VERSION 5.7 ;
  NOWIREEXTENSIONATPIN ON ;
  DIVIDERCHAR "/" ;
  BUSBITCHARS "[]" ;
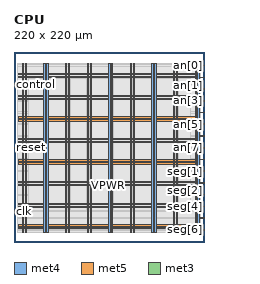
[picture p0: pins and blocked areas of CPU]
MACRO CPU
  CLASS BLOCK ;
  FOREIGN CPU ;
  ORIGIN 0.000 0.000 ;
  SIZE 220.000 BY 220.000 ;
  PIN VGND
    DIRECTION INOUT ;
    USE GROUND ;
    PORT
      LAYER met4 ;
        RECT 13.020 10.640 14.620 206.960 ;
    END
    PORT
      LAYER met4 ;
        RECT 38.020 10.640 39.620 206.960 ;
    END
    PORT
      LAYER met4 ;
        RECT 63.020 10.640 64.620 206.960 ;
    END
    PORT
      LAYER met4 ;
        RECT 88.020 10.640 89.620 206.960 ;
    END
    PORT
      LAYER met4 ;
        RECT 113.020 10.640 114.620 206.960 ;
    END
    PORT
      LAYER met4 ;
        RECT 138.020 10.640 139.620 206.960 ;
    END
    PORT
      LAYER met4 ;
        RECT 163.020 10.640 164.620 206.960 ;
    END
    PORT
      LAYER met4 ;
        RECT 188.020 10.640 189.620 206.960 ;
    END
    PORT
      LAYER met4 ;
        RECT 213.020 10.640 214.620 206.960 ;
    END
    PORT
      LAYER met5 ;
        RECT 5.280 18.380 214.620 19.980 ;
    END
    PORT
      LAYER met5 ;
        RECT 5.280 43.380 214.620 44.980 ;
    END
    PORT
      LAYER met5 ;
        RECT 5.280 68.380 214.620 69.980 ;
    END
    PORT
      LAYER met5 ;
        RECT 5.280 93.380 214.620 94.980 ;
    END
    PORT
      LAYER met5 ;
        RECT 5.280 118.380 214.620 119.980 ;
    END
    PORT
      LAYER met5 ;
        RECT 5.280 143.380 214.620 144.980 ;
    END
    PORT
      LAYER met5 ;
        RECT 5.280 168.380 214.620 169.980 ;
    END
    PORT
      LAYER met5 ;
        RECT 5.280 193.380 214.620 194.980 ;
    END
  END VGND
  PIN VPWR
    DIRECTION INOUT ;
    USE POWER ;
    PORT
      LAYER met4 ;
        RECT 9.720 10.640 11.320 206.960 ;
    END
    PORT
      LAYER met4 ;
        RECT 34.720 10.640 36.320 206.960 ;
    END
    PORT
      LAYER met4 ;
        RECT 59.720 10.640 61.320 206.960 ;
    END
    PORT
      LAYER met4 ;
        RECT 84.720 10.640 86.320 206.960 ;
    END
    PORT
      LAYER met4 ;
        RECT 109.720 10.640 111.320 206.960 ;
    END
    PORT
      LAYER met4 ;
        RECT 134.720 10.640 136.320 206.960 ;
    END
    PORT
      LAYER met4 ;
        RECT 159.720 10.640 161.320 206.960 ;
    END
    PORT
      LAYER met4 ;
        RECT 184.720 10.640 186.320 206.960 ;
    END
    PORT
      LAYER met4 ;
        RECT 209.720 10.640 211.320 206.960 ;
    END
    PORT
      LAYER met5 ;
        RECT 5.280 15.080 214.600 16.680 ;
    END
    PORT
      LAYER met5 ;
        RECT 5.280 40.080 214.600 41.680 ;
    END
    PORT
      LAYER met5 ;
        RECT 5.280 65.080 214.600 66.680 ;
    END
    PORT
      LAYER met5 ;
        RECT 5.280 90.080 214.600 91.680 ;
    END
    PORT
      LAYER met5 ;
        RECT 5.280 115.080 214.600 116.680 ;
    END
    PORT
      LAYER met5 ;
        RECT 5.280 140.080 214.600 141.680 ;
    END
    PORT
      LAYER met5 ;
        RECT 5.280 165.080 214.600 166.680 ;
    END
    PORT
      LAYER met5 ;
        RECT 5.280 190.080 214.600 191.680 ;
    END
  END VPWR
  PIN an[0]
    DIRECTION OUTPUT ;
    USE SIGNAL ;
    ANTENNADIFFAREA 0.340600 ;
    PORT
      LAYER met3 ;
        RECT 216.000 204.040 220.000 204.640 ;
    END
  END an[0]
  PIN an[1]
    DIRECTION OUTPUT ;
    USE SIGNAL ;
    ANTENNADIFFAREA 0.340600 ;
    PORT
      LAYER met3 ;
        RECT 216.000 190.440 220.000 191.040 ;
    END
  END an[1]
  PIN an[2]
    DIRECTION OUTPUT ;
    USE SIGNAL ;
    ANTENNADIFFAREA 0.340600 ;
    PORT
      LAYER met3 ;
        RECT 216.000 176.840 220.000 177.440 ;
    END
  END an[2]
  PIN an[3]
    DIRECTION OUTPUT ;
    USE SIGNAL ;
    ANTENNADIFFAREA 0.340600 ;
    PORT
      LAYER met3 ;
        RECT 216.000 163.240 220.000 163.840 ;
    END
  END an[3]
  PIN an[4]
    DIRECTION OUTPUT ;
    USE SIGNAL ;
    ANTENNADIFFAREA 0.340600 ;
    PORT
      LAYER met3 ;
        RECT 216.000 149.640 220.000 150.240 ;
    END
  END an[4]
  PIN an[5]
    DIRECTION OUTPUT ;
    USE SIGNAL ;
    ANTENNADIFFAREA 0.340600 ;
    PORT
      LAYER met3 ;
        RECT 216.000 136.040 220.000 136.640 ;
    END
  END an[5]
  PIN an[6]
    DIRECTION OUTPUT ;
    USE SIGNAL ;
    ANTENNADIFFAREA 0.340600 ;
    PORT
      LAYER met3 ;
        RECT 216.000 122.440 220.000 123.040 ;
    END
  END an[6]
  PIN an[7]
    DIRECTION OUTPUT ;
    USE SIGNAL ;
    ANTENNADIFFAREA 0.340600 ;
    PORT
      LAYER met3 ;
        RECT 216.000 108.840 220.000 109.440 ;
    END
  END an[7]
  PIN clk
    DIRECTION INPUT ;
    USE SIGNAL ;
    ANTENNAGATEAREA 0.852000 ;
    PORT
      LAYER met3 ;
        RECT 0.000 35.400 4.000 36.000 ;
    END
  END clk
  PIN control
    DIRECTION INPUT ;
    USE SIGNAL ;
    ANTENNAGATEAREA 0.196500 ;
    PORT
      LAYER met3 ;
        RECT 0.000 182.280 4.000 182.880 ;
    END
  END control
  PIN reset
    DIRECTION INPUT ;
    USE SIGNAL ;
    ANTENNAGATEAREA 0.393000 ;
    PORT
      LAYER met3 ;
        RECT 0.000 108.840 4.000 109.440 ;
    END
  END reset
  PIN seg[0]
    DIRECTION OUTPUT ;
    USE SIGNAL ;
    ANTENNADIFFAREA 0.340600 ;
    PORT
      LAYER met3 ;
        RECT 216.000 95.240 220.000 95.840 ;
    END
  END seg[0]
  PIN seg[1]
    DIRECTION OUTPUT ;
    USE SIGNAL ;
    ANTENNADIFFAREA 0.340600 ;
    PORT
      LAYER met3 ;
        RECT 216.000 81.640 220.000 82.240 ;
    END
  END seg[1]
  PIN seg[2]
    DIRECTION OUTPUT ;
    USE SIGNAL ;
    ANTENNADIFFAREA 0.340600 ;
    PORT
      LAYER met3 ;
        RECT 216.000 68.040 220.000 68.640 ;
    END
  END seg[2]
  PIN seg[3]
    DIRECTION OUTPUT ;
    USE SIGNAL ;
    ANTENNADIFFAREA 0.340600 ;
    PORT
      LAYER met3 ;
        RECT 216.000 54.440 220.000 55.040 ;
    END
  END seg[3]
  PIN seg[4]
    DIRECTION OUTPUT ;
    USE SIGNAL ;
    ANTENNADIFFAREA 0.340600 ;
    PORT
      LAYER met3 ;
        RECT 216.000 40.840 220.000 41.440 ;
    END
  END seg[4]
  PIN seg[5]
    DIRECTION OUTPUT ;
    USE SIGNAL ;
    ANTENNADIFFAREA 0.340600 ;
    PORT
      LAYER met3 ;
        RECT 216.000 27.240 220.000 27.840 ;
    END
  END seg[5]
  PIN seg[6]
    DIRECTION OUTPUT ;
    USE SIGNAL ;
    ANTENNADIFFAREA 0.340600 ;
    PORT
      LAYER met3 ;
        RECT 216.000 13.640 220.000 14.240 ;
    END
  END seg[6]
  OBS
      LAYER nwell ;
        RECT 5.330 10.795 214.550 206.805 ;
      LAYER li1 ;
        RECT 5.520 10.795 214.360 206.805 ;
      LAYER met1 ;
        RECT 4.210 10.640 215.670 206.960 ;
      LAYER met2 ;
        RECT 4.230 10.695 215.650 206.905 ;
      LAYER met3 ;
        RECT 3.990 205.040 216.000 206.885 ;
        RECT 3.990 203.640 215.600 205.040 ;
        RECT 3.990 191.440 216.000 203.640 ;
        RECT 3.990 190.040 215.600 191.440 ;
        RECT 3.990 183.280 216.000 190.040 ;
        RECT 4.400 181.880 216.000 183.280 ;
        RECT 3.990 177.840 216.000 181.880 ;
        RECT 3.990 176.440 215.600 177.840 ;
        RECT 3.990 164.240 216.000 176.440 ;
        RECT 3.990 162.840 215.600 164.240 ;
        RECT 3.990 150.640 216.000 162.840 ;
        RECT 3.990 149.240 215.600 150.640 ;
        RECT 3.990 137.040 216.000 149.240 ;
        RECT 3.990 135.640 215.600 137.040 ;
        RECT 3.990 123.440 216.000 135.640 ;
        RECT 3.990 122.040 215.600 123.440 ;
        RECT 3.990 109.840 216.000 122.040 ;
        RECT 4.400 108.440 215.600 109.840 ;
        RECT 3.990 96.240 216.000 108.440 ;
        RECT 3.990 94.840 215.600 96.240 ;
        RECT 3.990 82.640 216.000 94.840 ;
        RECT 3.990 81.240 215.600 82.640 ;
        RECT 3.990 69.040 216.000 81.240 ;
        RECT 3.990 67.640 215.600 69.040 ;
        RECT 3.990 55.440 216.000 67.640 ;
        RECT 3.990 54.040 215.600 55.440 ;
        RECT 3.990 41.840 216.000 54.040 ;
        RECT 3.990 40.440 215.600 41.840 ;
        RECT 3.990 36.400 216.000 40.440 ;
        RECT 4.400 35.000 216.000 36.400 ;
        RECT 3.990 28.240 216.000 35.000 ;
        RECT 3.990 26.840 215.600 28.240 ;
        RECT 3.990 14.640 216.000 26.840 ;
        RECT 3.990 13.240 215.600 14.640 ;
        RECT 3.990 10.715 216.000 13.240 ;
      LAYER met4 ;
        RECT 16.855 36.215 34.320 189.545 ;
        RECT 36.720 36.215 37.620 189.545 ;
        RECT 40.020 36.215 59.320 189.545 ;
        RECT 61.720 36.215 62.620 189.545 ;
        RECT 65.020 36.215 84.320 189.545 ;
        RECT 86.720 36.215 87.620 189.545 ;
        RECT 90.020 36.215 109.320 189.545 ;
        RECT 111.720 36.215 112.620 189.545 ;
        RECT 115.020 36.215 134.320 189.545 ;
        RECT 136.720 36.215 137.620 189.545 ;
        RECT 140.020 36.215 159.320 189.545 ;
        RECT 161.720 36.215 162.620 189.545 ;
        RECT 165.020 36.215 184.320 189.545 ;
        RECT 186.720 36.215 187.620 189.545 ;
        RECT 190.020 36.215 204.865 189.545 ;
  END
END CPU
END LIBRARY

